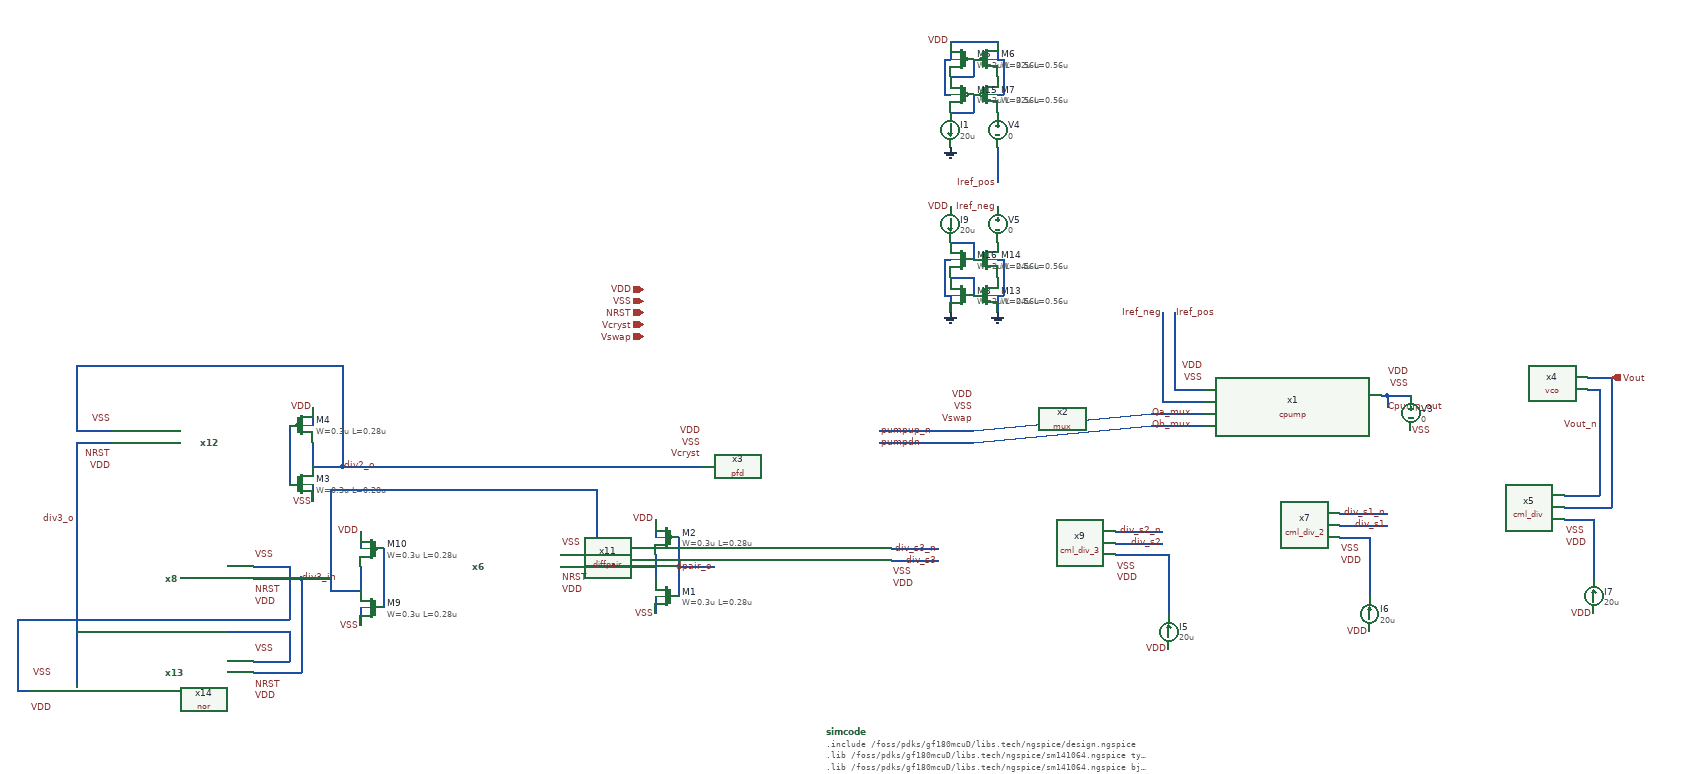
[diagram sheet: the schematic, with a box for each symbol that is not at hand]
v {xschem version=3.4.8RC file_version=1.3}
G {}
K {}
V {}
S {}
F {}
E {}
N 720 -350 810 -350 {lab=pumpup_n}
N 720 -330 810 -330 {lab=pumpdn}
N 760 -390 810 -390 {lab=Iref_pos}
N 760 -520 760 -390 {lab=Iref_pos}
N 740 -370 810 -370 {lab=Iref_neg}
N 740 -520 740 -370 {lab=Iref_neg}
N 1460 -410 1500 -410 {lab=Vout}
N 1500 -410 1500 -190 {lab=Vout}
N 1420 -190 1500 -190 {lab=Vout}
N 1460 -390 1480 -390 {lab=Vout_n}
N 1480 -390 1480 -210 {lab=Vout_n}
N 1420 -210 1480 -210 {lab=Vout_n}
N 660 -150 740 -150 {lab=div_s2_n}
N 660 -130 740 -130 {lab=div_s2}
N 660 -110 750 -110 {lab=#net1}
N 750 -110 750 -10 {lab=#net1}
N 1040 -140 1090 -140 {lab=#net2}
N 1090 -140 1090 -40 {lab=#net2}
N 1420 -170 1470 -170 {lab=#net3}
N 1470 -170 1470 -70 {lab=#net3}
N 1040 -180 1120 -180 {lab=div_s1_n}
N 1040 -160 1120 -160 {lab=div_s1}
N 280 -120 360 -120 {lab=div_s3_n}
N 280 -100 360 -100 {lab=div_s3}
N -80 -90 -20 -90 {lab=dpair_o}
N -120 -110 -120 -70 {lab=#net4}
N -80 -140 -80 -40 {lab=dpair_o}
N -120 -40 -120 -10 {lab=VSS}
N -120 -170 -120 -140 {lab=VDD}
N -700 -300 -700 -260 {lab=div2_o}
N -740 -330 -740 -230 {lab=#net5}
N -700 -230 -700 -200 {lab=VSS}
N -700 -360 -700 -330 {lab=VDD}
N -700 -260 -650 -260 {lab=div2_o}
N -650 -430 -650 -260 {lab=div2_o}
N -1100 -430 -650 -430 {lab=div2_o}
N -1100 -430 -1100 -320 {lab=div2_o}
N -1100 -320 -1040 -320 {lab=div2_o}
N -720 -70 -720 90 {lab=div3_in}
N -800 90 -720 90 {lab=div3_in}
N -1200 120 -1180 120 {lab=#net6}
N -1200 0 -1200 120 {lab=#net6}
N -1200 0 -740 0 {lab=#net6}
N -740 -90 -740 0 {lab=#net6}
N -800 -90 -740 -90 {lab=#net6}
N -1100 -30 -1100 110 {lab=div3_o}
N -1100 20 -740 20 {lab=div3_o}
N -740 20 -740 70 {lab=div3_o}
N -800 70 -740 70 {lab=div3_o}
N -1100 -160 -1100 -30 {lab=div3_o}
N -1100 -300 -1040 -300 {lab=div3_o}
N 1120 -380 1120 -360 {lab=Cpump_out}
N -800 -70 -720 -70 {lab=div3_in}
N -1100 -300 -1100 -160 {lab=div3_o}
N -220 -90 -120 -90 {lab=#net4}
N 260 -300 420 -300 {lab=pumpdn}
N 260 -320 420 -320 {lab=pumpup_n}
N 1110 -380 1120 -380 {lab=Cpump_out}
N 380 -980 460 -980 {lab=VDD}
N 460 -980 460 -950 {lab=VDD}
N 380 -980 380 -950 {lab=VDD}
N 460 -890 470 -890 {lab=VDD}
N 470 -950 470 -890 {lab=VDD}
N 460 -950 470 -950 {lab=VDD}
N 380 -580 420 -580 {lab=#net7}
N 420 -580 420 -550 {lab=#net7}
N 380 -550 380 -520 {lab=GND}
N 460 -610 470 -610 {lab=GND}
N 470 -610 470 -550 {lab=GND}
N 460 -550 470 -550 {lab=GND}
N 460 -800 460 -740 {lab=Iref_pos}
N 380 -920 420 -920 {lab=#net8}
N 420 -950 420 -920 {lab=#net8}
N 380 -860 420 -860 {lab=#net9}
N 420 -890 420 -860 {lab=#net9}
N 370 -890 380 -890 {lab=VDD}
N 370 -950 370 -890 {lab=VDD}
N 370 -950 380 -950 {lab=VDD}
N 380 -640 420 -640 {lab=#net10}
N 420 -640 420 -610 {lab=#net10}
N 370 -610 380 -610 {lab=GND}
N 370 -610 370 -550 {lab=GND}
N 370 -550 380 -550 {lab=GND}
N 460 -550 460 -520 {lab=GND}
N 1120 -380 1160 -380 {lab=Cpump_out}
N -620 -90 -620 -50 {lab=div3_in}
N -580 -120 -580 -20 {lab=#net11}
N -620 -20 -620 10 {lab=VSS}
N -620 -150 -620 -120 {lab=VDD}
N -670 -50 -620 -50 {lab=div3_in}
N -670 -220 -670 -50 {lab=div3_in}
N -670 -220 -220 -220 {lab=div3_in}
N -220 -220 -220 -110 {lab=div3_in}
N -280 -110 -220 -110 {lab=div3_in}
N -280 -90 -220 -90 {lab=#net4}
N -720 -70 -670 -70 {lab=div3_in}
N -650 -260 -40 -260 {lab=div2_o}
N 420 -320 720 -350 {lab=pumpup_n}
N 420 -300 720 -330 {lab=pumpdn}
C {blocks/pll/cpump.sym} 960 -380 0 0 {name=x1}
C {blocks/pll/mux.sym} 570 -340 0 0 {name=x2 spice_ignore=true}
C {ipin.sym} -140 -560 0 0 {name=p1 lab=VDD}
C {ipin.sym} -140 -540 0 0 {name=p2 lab=VSS}
C {lab_pin.sym} 810 -430 0 0 {name=p3 sig_type=std_logic lab=VDD}
C {lab_pin.sym} 810 -410 0 0 {name=p4 sig_type=std_logic lab=VSS}
C {ipin.sym} -140 -480 0 0 {name=p5 lab=Vswap}
C {ipin.sym} -140 -500 0 0 {name=p6 lab=Vcryst}
C {blocks/pll/pfd.sym} 110 -290 0 0 {name=x3}
C {lab_pin.sym} -40 -320 0 0 {name=p7 sig_type=std_logic lab=VDD}
C {lab_pin.sym} -40 -300 0 0 {name=p8 sig_type=std_logic lab=VSS}
C {blocks/pll/vco.sym} 1310 -400 0 0 {name=x4}
C {lab_pin.sym} 1160 -420 0 0 {name=p9 sig_type=std_logic lab=VDD}
C {lab_pin.sym} 1160 -400 0 0 {name=p10 sig_type=std_logic lab=VSS}
C {blocks/pll/cml_div.sym} 1270 -170 2 0 {name=x5}
C {lab_pin.sym} 1420 -130 0 1 {name=p11 sig_type=std_logic lab=VDD}
C {lab_pin.sym} 1420 -150 0 1 {name=p12 sig_type=std_logic lab=VSS}
C {lab_pin.sym} 1040 -100 0 1 {name=p13 sig_type=std_logic lab=VDD}
C {lab_pin.sym} 1040 -120 0 1 {name=p14 sig_type=std_logic lab=VSS}
C {lab_pin.sym} 660 -70 0 1 {name=p15 sig_type=std_logic lab=VDD}
C {lab_pin.sym} 660 -90 0 1 {name=p16 sig_type=std_logic lab=VSS}
C {code_shown.sym} 170 190 0 0 {name=simcode only_toplevel=true spice_ignore=false lvs_ignore=true

value=".include /foss/pdks/gf180mcuD/libs.tech/ngspice/design.ngspice
.lib /foss/pdks/gf180mcuD/libs.tech/ngspice/sm141064.ngspice typical
.lib /foss/pdks/gf180mcuD/libs.tech/ngspice/sm141064.ngspice bjt_typical
.lib /foss/pdks/gf180mcuD/libs.tech/ngspice/sm141064.ngspice diode_typical
.lib /foss/pdks/gf180mcuD/libs.tech/ngspice/sm141064.ngspice res_typical
.lib /foss/pdks/gf180mcuD/libs.tech/ngspice/sm141064.ngspice mimcap_typical
.lib /foss/pdks/gf180mcuD/libs.tech/ngspice/sm141064.ngspice moscap_typical

.option method = gear

V_VDD   VDD     0 DC 3.3
V_VSS   VSS     0 DC 0
V_NRST  NRST    0 DC 3.3
V_SWP   Vswap  0 DC 0
* V_CRYST Vcryst 0 SIN(1.65 1.65 50meg 0 0 0)
V_CRYST Vcryst 0 PULSE(0 3.3 0 1ns 1ns 9ns 20ns)

.control
    set temp = 25

    let freq = 1250meg
    let pers = 6000
    let persteps = 80

    let tper = 1 / freq
    let tfin = tper * pers
    let tstep = tper / persteps
    let tplotst = tfin - 192 * 2 * tper

    tran $&tstep $&tfin
    write pll_toplevel.raw

    * CML dividers
    * plot Vout div_s1 div_s2 div_s3 div_s4 xlimit $&tplotst $&tfin
    * CML to Digital conversion
    * plot Vout div_s4 dpair_o div3_in xlimit $&tplotst $&tfin
    * Digital dividers
    * plot div3_in div3_o div2_o xlimit $&tplotst $&tfin
    * Chirp generator
    plot div2_o vcryst*3/4 pumpup_n/2 pumpdn/4 xlimit $&tplotst $&tfin
    * plot qa qb qa_mux qb_mux xlimit $&tplotst $&tfin
    plot pumpup_n pumpdn*1/2 cpump_out xlimit $&tplotst $&tfin
.endc
"}
C {opin.sym} 1500 -410 0 0 {name=p42 lab=Vout}
C {isource.sym} 750 20 2 0 {name=I5 value=20u}
C {lab_pin.sym} 750 50 0 0 {name=p28 sig_type=std_logic lab=VDD}
C {isource.sym} 1090 -10 2 0 {name=I6 value=20u}
C {lab_pin.sym} 1090 20 0 0 {name=p29 sig_type=std_logic lab=VDD}
C {isource.sym} 1470 -40 2 0 {name=I7 value=20u}
C {lab_pin.sym} 1470 -10 0 0 {name=p30 sig_type=std_logic lab=VDD}
C {blocks/pll/cml_div_2.sym} 890 -140 2 0 {name=x7}
C {blocks/pll/cml_div_3.sym} 510 -110 2 0 {name=x9}
C {blocks/pll/diffpair.sym} 130 -90 2 0 {name=x11}
C {symbols/nfet_03v3.sym} -100 -40 0 1 {name=M1
L=0.28u
W=0.3u
nf=1
m=1
ad="'int((nf+1)/2) * W/nf * 0.18u'"
pd="'2*int((nf+1)/2) * (W/nf + 0.18u)'"
as="'int((nf+2)/2) * W/nf * 0.18u'"
ps="'2*int((nf+2)/2) * (W/nf + 0.18u)'"
nrd="'0.18u / W'" nrs="'0.18u / W'"
sa=0 sb=0 sd=0
model=nfet_03v3
spiceprefix=X
}
C {symbols/pfet_03v3.sym} -100 -140 2 0 {name=M2
L=0.28u
W=0.3u
nf=1
m=1
ad="'int((nf+1)/2) * W/nf * 0.18u'"
pd="'2*int((nf+1)/2) * (W/nf + 0.18u)'"
as="'int((nf+2)/2) * W/nf * 0.18u'"
ps="'2*int((nf+2)/2) * (W/nf + 0.18u)'"
nrd="'0.18u / W'" nrs="'0.18u / W'"
sa=0 sb=0 sd=0
model=pfet_03v3
spiceprefix=X
}
C {lab_pin.sym} -120 -170 1 0 {name=p45 sig_type=std_logic lab=VDD}
C {lab_pin.sym} -120 -10 1 1 {name=p46 sig_type=std_logic lab=VSS}
C {blocks/adc/encoder/sym/dff_encoder.sym} -890 -300 2 1 {name=x12}
C {symbols/nfet_03v3.sym} -720 -230 0 0 {name=M3
L=0.28u
W=0.3u
nf=1
m=1
ad="'int((nf+1)/2) * W/nf * 0.18u'"
pd="'2*int((nf+1)/2) * (W/nf + 0.18u)'"
as="'int((nf+2)/2) * W/nf * 0.18u'"
ps="'2*int((nf+2)/2) * (W/nf + 0.18u)'"
nrd="'0.18u / W'" nrs="'0.18u / W'"
sa=0 sb=0 sd=0
model=nfet_03v3
spiceprefix=X
}
C {symbols/pfet_03v3.sym} -720 -330 2 1 {name=M4
L=0.28u
W=0.3u
nf=1
m=1
ad="'int((nf+1)/2) * W/nf * 0.18u'"
pd="'2*int((nf+1)/2) * (W/nf + 0.18u)'"
as="'int((nf+2)/2) * W/nf * 0.18u'"
ps="'2*int((nf+2)/2) * (W/nf + 0.18u)'"
nrd="'0.18u / W'" nrs="'0.18u / W'"
sa=0 sb=0 sd=0
model=pfet_03v3
spiceprefix=X
}
C {lab_pin.sym} -700 -360 3 1 {name=p17 sig_type=std_logic lab=VDD}
C {lab_pin.sym} -700 -200 3 0 {name=p47 sig_type=std_logic lab=VSS}
C {lab_pin.sym} -1040 -340 0 0 {name=p48 sig_type=std_logic lab=VSS}
C {lab_pin.sym} -1040 -260 2 1 {name=p49 sig_type=std_logic lab=VDD}
C {lab_wire.sym} 1120 -180 0 0 {name=p20 sig_type=std_logic lab=div_s1_n}
C {lab_wire.sym} 1120 -160 0 0 {name=p21 sig_type=std_logic lab=div_s1}
C {lab_wire.sym} 740 -150 0 0 {name=p22 sig_type=std_logic lab=div_s2_n}
C {lab_wire.sym} 740 -130 0 0 {name=p23 sig_type=std_logic lab=div_s2}
C {lab_wire.sym} 360 -120 0 0 {name=p24 sig_type=std_logic lab=div_s3_n}
C {lab_wire.sym} 360 -100 0 0 {name=p25 sig_type=std_logic lab=div_s3}
C {lab_wire.sym} -20 -90 0 0 {name=p54 sig_type=std_logic lab=dpair_o}
C {lab_wire.sym} -720 -70 0 1 {name=p55 sig_type=std_logic lab=div3_in}
C {blocks/adc/encoder/sym/dff_encoder.sym} -950 -70 2 0 {name=x8}
C {blocks/adc/encoder/sym/dff_encoder.sym} -950 90 2 0 {name=x13}
C {blocks/pll/nor.sym} -1140 110 2 0 {name=x14}
C {lab_pin.sym} -800 -30 2 0 {name=p58 sig_type=std_logic lab=VDD}
C {lab_pin.sym} -800 130 2 0 {name=p59 sig_type=std_logic lab=VDD}
C {lab_pin.sym} -800 -110 0 1 {name=p60 sig_type=std_logic lab=VSS}
C {lab_pin.sym} -800 50 0 1 {name=p61 sig_type=std_logic lab=VSS}
C {lab_pin.sym} -800 -50 2 0 {name=p62 sig_type=std_logic lab=NRST}
C {lab_pin.sym} -800 110 2 0 {name=p63 sig_type=std_logic lab=NRST}
C {lab_pin.sym} -1040 -280 2 1 {name=p50 sig_type=std_logic lab=NRST}
C {ipin.sym} -140 -520 0 0 {name=p64 lab=NRST}
C {lab_wire.sym} -1100 -170 0 0 {name=p65 sig_type=std_logic lab=div3_o}
C {lab_pin.sym} -1140 150 3 0 {name=p56 sig_type=std_logic lab=VDD}
C {lab_pin.sym} -1140 90 3 1 {name=p66 sig_type=std_logic lab=VSS}
C {lab_wire.sym} -650 -260 0 1 {name=p19 sig_type=std_logic lab=div2_o}
C {lab_pin.sym} -40 -280 0 0 {name=p68 sig_type=std_logic lab=Vcryst}
C {lab_pin.sym} 420 -380 0 0 {name=p69 sig_type=std_logic lab=VDD
spice_ignore=true}
C {lab_pin.sym} 420 -360 0 0 {name=p70 sig_type=std_logic lab=VSS
spice_ignore=true}
C {lab_pin.sym} 420 -340 0 0 {name=p71 sig_type=std_logic lab=Vswap
spice_ignore=true}
C {lab_wire.sym} 1480 -330 0 0 {name=p18 sig_type=std_logic lab=Vout_n}
C {lab_wire.sym} 790 -350 2 1 {name=p72 sig_type=std_logic lab=Qa_mux
spice_ignore=true}
C {lab_wire.sym} 790 -330 2 1 {name=p73 sig_type=std_logic lab=Qb_mux
spice_ignore=true}
C {lab_wire.sym} 1120 -360 2 0 {name=p74 sig_type=std_logic lab=Cpump_out}
C {lab_wire.sym} 740 -520 0 0 {name=p38 sig_type=std_logic lab=Iref_neg}
C {lab_wire.sym} 760 -520 0 1 {name=p39 sig_type=std_logic lab=Iref_pos}
C {lab_wire.sym} 260 -320 0 1 {name=p31 sig_type=std_logic lab=pumpup_n}
C {lab_wire.sym} 260 -300 0 1 {name=p41 sig_type=std_logic lab=pumpdn}
C {vsource.sym} 1160 -350 0 0 {name=V3 value=0 savecurrent=false spice_ignore=true}
C {lab_pin.sym} 1160 -320 0 1 {name=p57 sig_type=std_logic lab=VSS}
C {isource.sym} 380 -830 0 0 {name=I1 value=20u
lvs_ignore=true}
C {lab_wire.sym} 380 -980 0 0 {name=p67 sig_type=std_logic lab=VDD}
C {symbols/pfet_03v3.sym} 400 -950 0 1 {name=M5
L=0.56u
W=2u
nf=1
m=1
ad="'int((nf+1)/2) * W/nf * 0.18u'"
pd="'2*int((nf+1)/2) * (W/nf + 0.18u)'"
as="'int((nf+2)/2) * W/nf * 0.18u'"
ps="'2*int((nf+2)/2) * (W/nf + 0.18u)'"
nrd="'0.18u / W'" nrs="'0.18u / W'"
sa=0 sb=0 sd=0
model=pfet_03v3
spiceprefix=X
}
C {symbols/pfet_03v3.sym} 440 -950 0 0 {name=M6
L=0.56u
W=32u
nf=16
m=1
ad="'int((nf+1)/2) * W/nf * 0.18u'"
pd="'2*int((nf+1)/2) * (W/nf + 0.18u)'"
as="'int((nf+2)/2) * W/nf * 0.18u'"
ps="'2*int((nf+2)/2) * (W/nf + 0.18u)'"
nrd="'0.18u / W'" nrs="'0.18u / W'"
sa=0 sb=0 sd=0
model=pfet_03v3
spiceprefix=X
}
C {gnd.sym} 380 -800 0 0 {name=l1 lab=GND
lvs_ignore=true}
C {symbols/pfet_03v3.sym} 440 -890 0 0 {name=M7
L=0.56u
W=32u
nf=16
m=1
ad="'int((nf+1)/2) * W/nf * 0.18u'"
pd="'2*int((nf+1)/2) * (W/nf + 0.18u)'"
as="'int((nf+2)/2) * W/nf * 0.18u'"
ps="'2*int((nf+2)/2) * (W/nf + 0.18u)'"
nrd="'0.18u / W'" nrs="'0.18u / W'"
sa=0 sb=0 sd=0
model=pfet_03v3
spiceprefix=X
}
C {vsource.sym} 460 -830 0 0 {name=V4 value=0 savecurrent=false}
C {isource.sym} 380 -670 0 0 {name=I9 value=20u
lvs_ignore=true}
C {lab_wire.sym} 380 -700 0 0 {name=p75 sig_type=std_logic lab=VDD}
C {symbols/nfet_03v3.sym} 400 -550 0 1 {name=M8
L=0.56u
W=2u
nf=1
m=1
ad="'int((nf+1)/2) * W/nf * 0.18u'"
pd="'2*int((nf+1)/2) * (W/nf + 0.18u)'"
as="'int((nf+2)/2) * W/nf * 0.18u'"
ps="'2*int((nf+2)/2) * (W/nf + 0.18u)'"
nrd="'0.18u / W'" nrs="'0.18u / W'"
sa=0 sb=0 sd=0
model=nfet_03v3
spiceprefix=X
}
C {symbols/nfet_03v3.sym} 440 -550 0 0 {name=M13
L=0.56u
W=24u
nf=12
m=1
ad="'int((nf+1)/2) * W/nf * 0.18u'"
pd="'2*int((nf+1)/2) * (W/nf + 0.18u)'"
as="'int((nf+2)/2) * W/nf * 0.18u'"
ps="'2*int((nf+2)/2) * (W/nf + 0.18u)'"
nrd="'0.18u / W'" nrs="'0.18u / W'"
sa=0 sb=0 sd=0
model=nfet_03v3
spiceprefix=X
}
C {gnd.sym} 380 -520 0 0 {name=l2 lab=GND
lvs_ignore=true}
C {lab_wire.sym} 460 -700 0 0 {name=p78 sig_type=std_logic lab=Iref_neg}
C {symbols/nfet_03v3.sym} 440 -610 0 0 {name=M14
L=0.56u
W=24u
nf=12
m=1
ad="'int((nf+1)/2) * W/nf * 0.18u'"
pd="'2*int((nf+1)/2) * (W/nf + 0.18u)'"
as="'int((nf+2)/2) * W/nf * 0.18u'"
ps="'2*int((nf+2)/2) * (W/nf + 0.18u)'"
nrd="'0.18u / W'" nrs="'0.18u / W'"
sa=0 sb=0 sd=0
model=nfet_03v3
spiceprefix=X
}
C {vsource.sym} 460 -670 0 0 {name=V5 value=0 savecurrent=false}
C {symbols/pfet_03v3.sym} 400 -890 0 1 {name=M15
L=0.56u
W=2u
nf=1
m=1
ad="'int((nf+1)/2) * W/nf * 0.18u'"
pd="'2*int((nf+1)/2) * (W/nf + 0.18u)'"
as="'int((nf+2)/2) * W/nf * 0.18u'"
ps="'2*int((nf+2)/2) * (W/nf + 0.18u)'"
nrd="'0.18u / W'" nrs="'0.18u / W'"
sa=0 sb=0 sd=0
model=pfet_03v3
spiceprefix=X
}
C {lab_wire.sym} 460 -740 0 0 {name=p79 sig_type=std_logic lab=Iref_pos}
C {symbols/nfet_03v3.sym} 400 -610 0 1 {name=M16
L=0.56u
W=2u
nf=1
m=1
ad="'int((nf+1)/2) * W/nf * 0.18u'"
pd="'2*int((nf+1)/2) * (W/nf + 0.18u)'"
as="'int((nf+2)/2) * W/nf * 0.18u'"
ps="'2*int((nf+2)/2) * (W/nf + 0.18u)'"
nrd="'0.18u / W'" nrs="'0.18u / W'"
sa=0 sb=0 sd=0
model=nfet_03v3
spiceprefix=X
}
C {gnd.sym} 460 -520 0 0 {name=l4 lab=GND
lvs_ignore=true}
C {blocks/adc/encoder/sym/dff_encoder.sym} -430 -90 2 0 {name=x6}
C {symbols/nfet_03v3.sym} -600 -20 0 1 {name=M9
L=0.28u
W=0.3u
nf=1
m=1
ad="'int((nf+1)/2) * W/nf * 0.18u'"
pd="'2*int((nf+1)/2) * (W/nf + 0.18u)'"
as="'int((nf+2)/2) * W/nf * 0.18u'"
ps="'2*int((nf+2)/2) * (W/nf + 0.18u)'"
nrd="'0.18u / W'" nrs="'0.18u / W'"
sa=0 sb=0 sd=0
model=nfet_03v3
spiceprefix=X
}
C {symbols/pfet_03v3.sym} -600 -120 2 0 {name=M10
L=0.28u
W=0.3u
nf=1
m=1
ad="'int((nf+1)/2) * W/nf * 0.18u'"
pd="'2*int((nf+1)/2) * (W/nf + 0.18u)'"
as="'int((nf+2)/2) * W/nf * 0.18u'"
ps="'2*int((nf+2)/2) * (W/nf + 0.18u)'"
nrd="'0.18u / W'" nrs="'0.18u / W'"
sa=0 sb=0 sd=0
model=pfet_03v3
spiceprefix=X
}
C {lab_pin.sym} -620 -150 1 0 {name=p35 sig_type=std_logic lab=VDD}
C {lab_pin.sym} -620 10 1 1 {name=p36 sig_type=std_logic lab=VSS}
C {lab_pin.sym} -280 -130 0 1 {name=p37 sig_type=std_logic lab=VSS}
C {lab_pin.sym} -280 -50 2 0 {name=p40 sig_type=std_logic lab=VDD}
C {lab_pin.sym} -280 -70 2 0 {name=p43 sig_type=std_logic lab=NRST}
C {lab_pin.sym} 280 -60 0 1 {name=p26 sig_type=std_logic lab=VDD}
C {lab_pin.sym} 280 -80 0 1 {name=p27 sig_type=std_logic lab=VSS}
